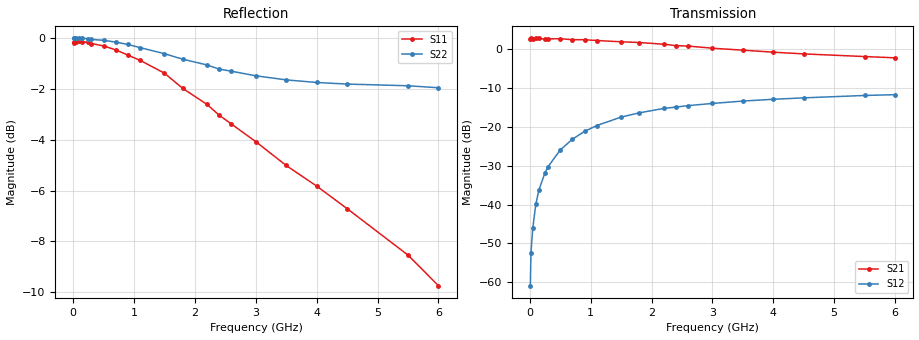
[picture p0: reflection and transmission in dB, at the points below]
! SIEMENS Discrete & RF Semiconductors
! BFY180
! Si NPN RF Bipolar Junction Transistor in MICRO-X
! VCE = 1.5 V  IC = 0.4 mA
! Common Emitter S-Parameters:  May  1997
# GHz  S  MA  R  50
!  f  S11  S21  S12  S22
! GHz  MAG  ANG  MAG  ANG  MAG  ANG  MAG  ANG
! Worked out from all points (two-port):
!   36 points, 10 MHz to 6 GHz, reference 50 ohm
!   highest |S21| = 2.85 dB at 100 MHz (marker M1); lowest = -2.2 dB at 6 GHz (marker M2)
!   |S21| within 3 dB of the highest: start of sweep to 3.459 GHz
!   lowest |S11| = -9.7 dB at 6 GHz (marker M3), VSWR 1.97, Z = 28.7 - j15.1 ohm
!   |S11| at or under -10 dB: nowhere
!   |S22| runs from -1.9 to 0.0 dB; largest |S21 - S12| = 1.4
!   S11 on the Smith chart (normalised r, x): 10 MHz: open; 700 MHz: 0.70, -5.03; 1.5 GHz: 0.51, -2.29; 2.4 GHz: 0.51, -1.34; 4 GHz: 0.52, -0.72; 6 GHz: 0.57, -0.30
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0.01  0.9831 -0.3  1.367 180.0  0.0009 89.6  0.9993 -0.1
0.02  0.9803 -0.6  1.386 179.2  0.0024 87.7  0.9999 -0.4
0.05  0.9827 -1.3  1.379 178.2  0.005 83.5  0.9993 -1.1
0.1  0.9884 -3.1  1.388 176.1  0.0101 89.2  0.9995 -2.3
0.15  0.9842 -4.9  1.383 174.1  0.0154 86.4  0.9999 -3.3
0.25  0.9814 -8.0  1.359 169.9  0.0255 84.1  0.9985 -5.7
0.3  0.9768 -9.4  1.369 167.5  0.0307 82.7  0.9952 -6.8
0.5  0.9661 -15.9  1.372 159.2  0.0504 77.2  0.9911 -11.2
0.7  0.9489 -22.1  1.335 151.5  0.0696 72.2  0.9831 -15.5
0.9  0.9268 -28.0  1.334 143.6  0.0877 67.4  0.9727 -19.9
1.1  0.9051 -33.9  1.302 136.2  0.1043 62.8  0.9589 -24.0
1.5  0.8539 -45.4  1.254 121.5  0.1341 53.5  0.9328 -32.1
1.8  0.7969 -54.1  1.227 110.5  0.1523 47.9  0.9097 -37.6
2.2  0.7409 -63.8  1.166 96.9  0.1733 40.3  0.8863 -44.6
2.4  0.7055 -68.6  1.119 90.7  0.1805 37.2  0.8696 -47.8
2.6  0.678 -73.0  1.104 84.8  0.1885 34.3  0.8614 -50.7
3  0.6258 -81.1  1.036 74.0  0.2011 28.6  0.8438 -56.7
3.5  0.5616 -90.1  0.978 60.9  0.2159 22.6  0.8282 -63.4
4  0.5115 -98.6  0.921 49.6  0.2276 16.9  0.8185 -70.3
4.5  0.4618 -106.6  0.875 39.1  0.2374 11.8  0.8126 -77.1
5.5  0.374 -123.6  0.809 19.7  0.2549 2.0  0.8064 -91.2
6  0.3255 -133.8  0.779 11.0  0.2609 -3.0  0.7991 -98.2
